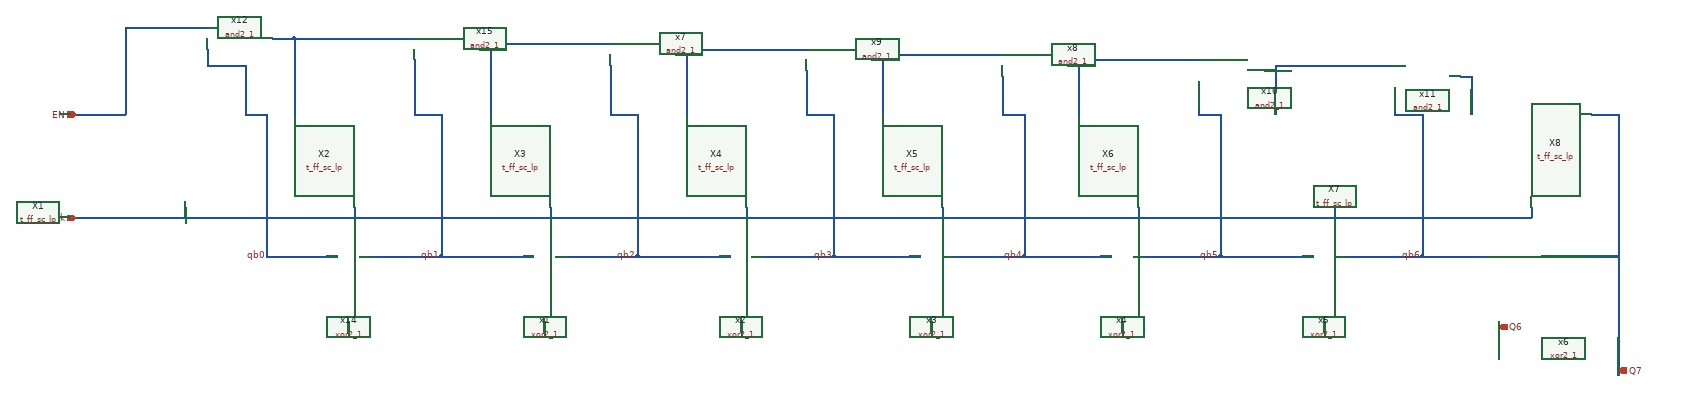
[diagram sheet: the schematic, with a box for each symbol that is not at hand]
v {xschem version=2.9.9 file_version=1.2 }
G {}
K {}
V {}
S {}
E {}
N 2100 -440 3210 -440 { lab=Clk}
N 680 -440 760 -440 { lab=Clk}
N 760 -440 1870 -440 { lab=Clk}
N 1190 -250 1190 -230 { lab=Q0}
N 1550 -250 1550 -230 { lab=Q1}
N 1910 -250 1910 -230 { lab=Q2}
N 2610 -250 2610 -230 { lab=Q4}
N 2980 -250 2980 -230 { lab=Q5}
N 3300 -250 3300 -230 { lab=Q6}
N 3360 -460 3360 -440 { lab=Clk}
N 3000 -460 3000 -440 { lab=Clk}
N 2640 -460 2640 -440 { lab=Clk}
N 2280 -460 2280 -440 { lab=Clk}
N 1920 -460 1920 -440 { lab=Clk}
N 1560 -460 1560 -440 { lab=Clk}
N 890 -460 890 -440 { lab=Clk}
N 1200 -460 1200 -440 { lab=Clk}
N 680 -630 780 -630 { lab=EN}
N 1090 -770 1090 -630 { lab=qb0}
N 1090 -770 1310 -770 { lab=qb0}
N 1450 -760 1450 -630 { lab=#net1}
N 1450 -760 1670 -760 { lab=#net1}
N 1810 -750 1810 -630 { lab=#net2}
N 1810 -750 2030 -750 { lab=#net2}
N 2170 -740 2170 -630 { lab=#net3}
N 2170 -740 2390 -740 { lab=#net3}
N 2530 -730 2730 -730 { lab=#net4}
N 2730 -730 2750 -730 { lab=#net4}
N 2530 -730 2530 -630 { lab=#net4}
N 2890 -720 2890 -630 { lab=#net5}
N 2890 -720 3110 -720 { lab=#net5}
N 3470 -630 3520 -630 { lab=Q7}
N 3520 -630 3520 -150 { lab=Q7}
N 1040 -630 1040 -370 { lab=qb0}
N 1310 -630 1360 -630 { lab=qb1}
N 1360 -630 1360 -370 { lab=qb1}
N 1670 -630 1720 -630 { lab=qb2}
N 1720 -630 1720 -370 { lab=qb2}
N 2030 -630 2080 -630 { lab=qb3}
N 2080 -630 2080 -370 { lab=qb3}
N 1870 -440 2100 -440 { lab=Clk}
N 3210 -440 3360 -440 { lab=Clk}
N 2390 -630 2430 -630 { lab=qb4}
N 2430 -630 2430 -370 { lab=qb4}
N 2750 -630 2790 -630 { lab=qb5}
N 2790 -630 2790 -370 { lab=qb5}
N 3110 -630 3160 -630 { lab=qb6}
N 3160 -630 3160 -370 { lab=qb6}
N 1210 -370 1360 -370 { lab=qb1}
N 1570 -370 1720 -370 { lab=qb2}
N 1720 -370 1870 -370 { lab=qb2}
N 1930 -370 2080 -370 { lab=qb3}
N 2080 -370 2210 -370 { lab=qb3}
N 2280 -370 2430 -370 { lab=qb4}
N 2630 -370 2790 -370 { lab=qb5}
N 3000 -370 3160 -370 { lab=qb6}
N 3160 -370 3260 -370 { lab=qb6}
N 3320 -370 3520 -370 { lab=Q7}
N 1040 -370 1170 -370 { lab=qb0}
N 1360 -370 1530 -370 { lab=qb1}
N 1870 -370 1890 -370 { lab=qb2}
N 2260 -250 2260 -230 { lab=Q3}
N 2210 -370 2240 -370 { lab=qb3}
N 2430 -370 2590 -370 { lab=qb4}
N 2790 -370 2960 -370 { lab=qb5}
N 3260 -370 3280 -370 { lab=qb6}
N 1310 -730 1310 -630 { lab=qb1}
N 1430 -750 1450 -750 { lab=#net1}
N 1670 -720 1670 -630 { lab=qb2}
N 1790 -740 1810 -740 { lab=#net2}
N 2030 -710 2030 -630 { lab=qb3}
N 2150 -730 2170 -730 { lab=#net3}
N 2390 -700 2390 -630 { lab=qb4}
N 2510 -720 2530 -720 { lab=#net4}
N 2750 -690 2750 -630 { lab=qb5}
N 2870 -710 2890 -710 { lab=#net5}
N 3110 -680 3110 -630 { lab=qb6}
N 3230 -700 3250 -700 { lab=#net6}
N 3250 -700 3250 -630 { lab=#net6}
N 780 -790 780 -630 {}
N 780 -790 930 -790 {}
N 930 -750 930 -720 {}
N 930 -720 1000 -720 {}
N 1000 -720 1000 -630 {}
N 1000 -630 1040 -630 {}
N 1050 -770 1090 -770 {}
C {devices/ipin.sym} 690 -440 0 0 {name=p11 lab=Clk}
C {devices/ipin.sym} 690 -630 0 0 {name=p12 lab=EN}
C {devices/opin.sym} 1190 -240 1 0 {name=p13 lab=Q0}
C {devices/opin.sym} 1550 -240 1 0 {name=p14 lab=Q1}
C {devices/opin.sym} 1910 -240 1 0 {name=p15 lab=Q2}
C {devices/opin.sym} 2610 -240 1 0 {name=p17 lab=Q4}
C {devices/opin.sym} 2980 -240 1 0 {name=p18 lab=Q5}
C {devices/opin.sym} 3300 -240 1 0 {name=p19 lab=Q6}
C {devices/opin.sym} 3520 -160 1 0 {name=p20 lab=Q7}
C {devices/lab_pin.sym} 1040 -370 3 0 {name=l8 sig_type=std_logic lab=qb0}
C {devices/lab_pin.sym} 1360 -370 3 0 {name=l9 sig_type=std_logic lab=qb1}
C {devices/lab_pin.sym} 1720 -370 3 0 {name=l10 sig_type=std_logic lab=qb2}
C {devices/lab_pin.sym} 2080 -370 3 0 {name=l11 sig_type=std_logic lab=qb3}
C {devices/lab_pin.sym} 2430 -370 3 0 {name=l12 sig_type=std_logic lab=qb4}
C {devices/lab_pin.sym} 2790 -370 3 0 {name=l13 sig_type=std_logic lab=qb5}
C {devices/lab_pin.sym} 3160 -370 3 0 {name=l14 sig_type=std_logic lab=qb6}
C {T_flip_flop/t_ff_sc_lp.sym} 890 -590 0 0 {name=X1}
C {T_flip_flop/t_ff_sc_lp.sym} 1200 -590 0 0 {name=X2}
C {T_flip_flop/t_ff_sc_lp.sym} 1560 -590 0 0 {name=X3}
C {T_flip_flop/t_ff_sc_lp.sym} 1920 -590 0 0 {name=X4}
C {T_flip_flop/t_ff_sc_lp.sym} 2280 -590 0 0 {name=X5}
C {T_flip_flop/t_ff_sc_lp.sym} 2640 -590 0 0 {name=X6}
C {T_flip_flop/t_ff_sc_lp.sym} 3000 -590 0 0 {name=X7}
C {T_flip_flop/t_ff_sc_lp.sym} 3360 -590 0 0 {name=X8}
C {devices/opin.sym} 2260 -240 1 0 {name=p1 lab=Q3}
C {sky130_stdcells/xor2_1.sym} 1190 -310 1 0 {name=x14 VGND=GND VNB=GND VPB=VDD VPWR=VDD prefix=sky130_fd_sc_lp__ }
C {sky130_stdcells/and2_1.sym} 1370 -750 0 0 {name=x15 VGND=GND VNB=GND VPB=VDD VPWR=VDD prefix=sky130_fd_sc_lp__ }
C {sky130_stdcells/xor2_1.sym} 1550 -310 1 0 {name=x1 VGND=GND VNB=GND VPB=VDD VPWR=VDD prefix=sky130_fd_sc_lp__ }
C {sky130_stdcells/xor2_1.sym} 1910 -310 1 0 {name=x2 VGND=GND VNB=GND VPB=VDD VPWR=VDD prefix=sky130_fd_sc_lp__  }
C {sky130_stdcells/xor2_1.sym} 2260 -310 1 0 {name=x3 VGND=GND VNB=GND VPB=VDD VPWR=VDD prefix=sky130_fd_sc_lp__ }
C {sky130_stdcells/xor2_1.sym} 2610 -310 1 0 {name=x4 VGND=GND VNB=GND VPB=VDD VPWR=VDD prefix=sky130_fd_sc_lp__ }
C {sky130_stdcells/xor2_1.sym} 2980 -310 1 0 {name=x5 VGND=GND VNB=GND VPB=VDD VPWR=VDD prefix=sky130_fd_sc_lp__ }
C {sky130_stdcells/xor2_1.sym} 3300 -310 1 0 {name=x6 VGND=GND VNB=GND VPB=VDD VPWR=VDD prefix=sky130_fd_sc_lp__ }
C {sky130_stdcells/and2_1.sym} 1730 -740 0 0 {name=x7 VGND=GND VNB=GND VPB=VDD VPWR=VDD prefix=sky130_fd_sc_lp__ }
C {sky130_stdcells/and2_1.sym} 2450 -720 0 0 {name=x8 VGND=GND VNB=GND VPB=VDD VPWR=VDD prefix=sky130_fd_sc_lp__ }
C {sky130_stdcells/and2_1.sym} 2090 -730 0 0 {name=x9 VGND=GND VNB=GND VPB=VDD VPWR=VDD prefix=sky130_fd_sc_lp__  }
C {sky130_stdcells/and2_1.sym} 2810 -710 0 0 {name=x10 VGND=GND VNB=GND VPB=VDD VPWR=VDD prefix=sky130_fd_sc_lp__ }
C {sky130_stdcells/and2_1.sym} 3170 -700 0 0 {name=x11 VGND=GND VNB=GND VPB=VDD VPWR=VDD prefix=sky130_fd_sc_lp__ }
C {sky130_stdcells/and2_1.sym} 990 -770 0 0 {name=x12 VGND=GND VNB=GND VPB=VDD VPWR=VDD prefix=sky130_fd_sc_lp__ }
